VERSION 5.7 ;
  NOWIREEXTENSIONATPIN ON ;
  DIVIDERCHAR "/" ;
  BUSBITCHARS "[]" ;
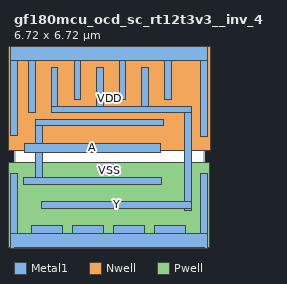
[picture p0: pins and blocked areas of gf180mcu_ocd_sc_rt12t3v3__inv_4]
MACRO gf180mcu_ocd_sc_rt12t3v3__inv_4
  CLASS CORE ;
  FOREIGN gf180mcu_ocd_sc_rt12t3v3__inv_4 ;
  ORIGIN 0.000 0.000 ;
  SIZE 6.720 BY 6.720 ;
  SYMMETRY X Y ;
  SITE unithd ;
  PIN A
    DIRECTION INPUT ;
    USE SIGNAL ;
    ANTENNAGATEAREA 6.683600 ;
    PORT
      LAYER Metal1 ;
        RECT 0.770 4.115 5.285 4.345 ;
        RECT 0.770 3.490 1.000 4.115 ;
        RECT 0.370 3.160 5.190 3.490 ;
        RECT 0.770 2.285 1.000 3.160 ;
        RECT 0.350 2.040 5.200 2.285 ;
    END
  END A
  PIN Y
    DIRECTION OUTPUT ;
    USE SIGNAL ;
    ANTENNADIFFAREA 3.902400 ;
    PORT
      LAYER Metal1 ;
        RECT 1.325 4.805 1.555 6.180 ;
        RECT 2.925 4.805 3.155 6.180 ;
        RECT 4.525 4.805 4.755 6.160 ;
        RECT 1.325 4.575 6.290 4.805 ;
        RECT 6.030 1.425 6.290 4.575 ;
        RECT 0.985 1.195 6.290 1.425 ;
        RECT 6.030 1.120 6.290 1.195 ;
    END
  END Y
  PIN VDD
    DIRECTION INOUT ;
    USE POWER ;
    SHAPE ABUTMENT ;
    PORT
      LAYER Nwell ;
        RECT -0.610 3.245 7.330 7.330 ;
      LAYER Metal1 ;
        RECT -0.115 6.420 6.835 7.020 ;
        RECT -0.115 3.750 0.115 6.420 ;
        RECT 0.525 4.580 0.755 6.420 ;
        RECT 2.125 5.035 2.355 6.420 ;
        RECT 3.725 5.035 3.955 6.420 ;
        RECT 5.325 5.035 5.555 6.420 ;
        RECT 6.605 3.745 6.835 6.420 ;
    END
  END VDD
  PIN VSS
    DIRECTION INOUT ;
    USE GROUND ;
    SHAPE ABUTMENT ;
    PORT
      LAYER Pwell ;
        RECT -0.180 -0.180 6.900 2.815 ;
        RECT 0.000 -0.300 6.720 -0.180 ;
      LAYER Metal1 ;
        RECT -0.115 0.300 0.115 2.410 ;
        RECT 0.605 0.300 1.715 0.585 ;
        RECT 2.065 0.300 3.165 0.585 ;
        RECT 3.515 0.300 4.615 0.585 ;
        RECT 4.965 0.300 6.065 0.585 ;
        RECT 6.605 0.300 6.835 2.410 ;
        RECT -0.115 -0.300 6.835 0.300 ;
    END
  END VSS
END gf180mcu_ocd_sc_rt12t3v3__inv_4
END LIBRARY

